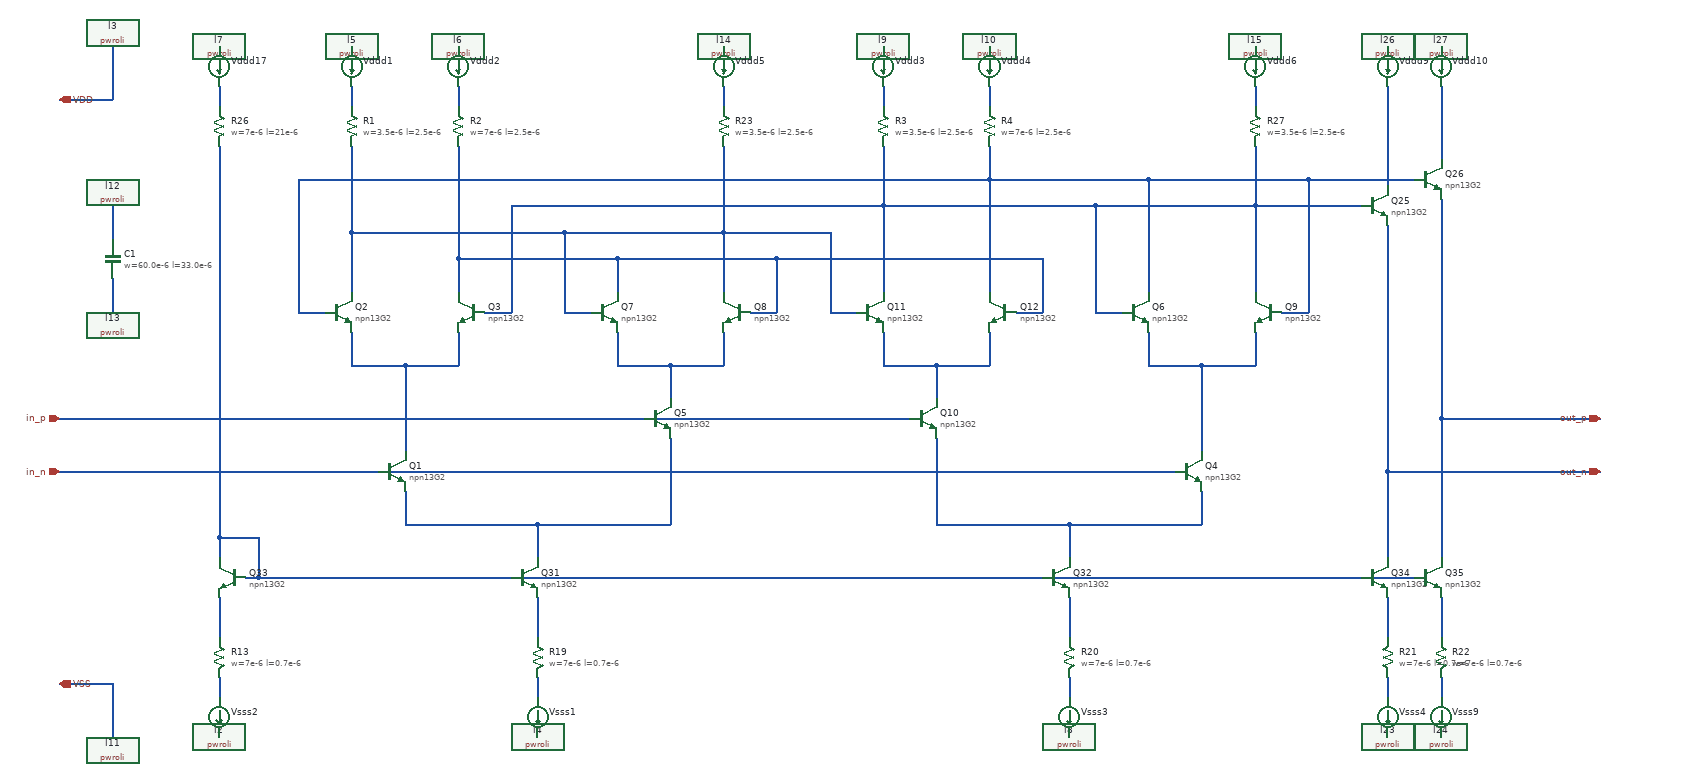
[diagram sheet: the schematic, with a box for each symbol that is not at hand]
v {xschem version=3.4.7RC file_version=1.2
*
* This file is part of XSCHEM,
* a schematic capture and Spice/Vhdl/Verilog netlisting tool for circuit
* simulation.
* Copyright (C) 1998-2023 Stefan Frederik Schippers
*
* This program is free software; you can redistribute it and/or modify
* it under the terms of the GNU General Public License as published by
* the Free Software Foundation; either version 2 of the License, or
* (at your option) any later version.
*
* This program is distributed in the hope that it will be useful,
* but WITHOUT ANY WARRANTY; without even the implied warranty of
* MERCHANTABILITY or FITNESS FOR A PARTICULAR PURPOSE.  See the
* GNU General Public License for more details.
*
* You should have received a copy of the GNU General Public License
* along with this program; if not, write to the Free Software
* Foundation, Inc., 51 Franklin Street, Fifth Floor, Boston, MA 02110-1301 USA
}
G {}
K {}
V {}
S {}
E {}
N 1160 -800 1240 -800 {lab=#net1}
N 1160 -800 1160 -750 {lab=#net1}
N 1080 -800 1160 -800 {lab=#net1}
N 1080 -850 1080 -800 {lab=#net1}
N 1240 -850 1240 -800 {lab=#net1}
N 760 -800 840 -800 {lab=#net2}
N 760 -800 760 -670 {lab=#net2}
N 680 -800 760 -800 {lab=#net2}
N 680 -850 680 -800 {lab=#net2}
N 840 -850 840 -800 {lab=#net2}
N 680 -1000 680 -910 {lab=#net3}
N 840 -960 840 -910 {lab=#net4}
N 680 -1130 680 -1000 {lab=#net3}
N 1240 -1000 1240 -910 {lab=#net3}
N 840 -960 1080 -960 {lab=#net4}
N 840 -1130 840 -960 {lab=#net4}
N 1080 -960 1080 -910 {lab=#net4}
N 1000 -880 1040 -880 {lab=#net3}
N 1000 -1000 1000 -880 {lab=#net3}
N 680 -1000 1000 -1000 {lab=#net3}
N 1080 -960 1320 -960 {lab=#net4}
N 1320 -960 1320 -880 {lab=#net4}
N 1280 -880 1320 -880 {lab=#net4}
N 680 -1220 680 -1190 {lab=VDD}
N 840 -1220 840 -1190 {lab=VDD}
N 1960 -800 2040 -800 {lab=#net5}
N 1960 -800 1960 -670 {lab=#net5}
N 1880 -800 1960 -800 {lab=#net5}
N 1880 -850 1880 -800 {lab=#net5}
N 2040 -850 2040 -800 {lab=#net5}
N 1560 -800 1640 -800 {lab=#net6}
N 1560 -800 1560 -750 {lab=#net6}
N 1480 -800 1560 -800 {lab=#net6}
N 1480 -850 1480 -800 {lab=#net6}
N 1640 -850 1640 -800 {lab=#net6}
N 1480 -1040 1480 -910 {lab=#net7}
N 1640 -1080 1640 -910 {lab=#net8}
N 1800 -1040 2040 -1040 {lab=#net7}
N 1480 -1130 1480 -1040 {lab=#net7}
N 1640 -1130 1640 -1080 {lab=#net8}
N 1880 -1080 1880 -910 {lab=#net8}
N 1800 -880 1840 -880 {lab=#net7}
N 1800 -1040 1800 -880 {lab=#net7}
N 1880 -1080 2120 -1080 {lab=#net8}
N 2120 -1080 2120 -880 {lab=#net8}
N 2080 -880 2120 -880 {lab=#net8}
N 1480 -1220 1480 -1190 {lab=VDD}
N 1640 -1220 1640 -1190 {lab=VDD}
N 1680 -880 1720 -880 {lab=#net4}
N 1000 -1000 1240 -1000 {lab=#net3}
N 600 -880 640 -880 {lab=#net8}
N 880 -880 920 -880 {lab=#net7}
N 1640 -1080 1880 -1080 {lab=#net8}
N 1320 -960 1720 -960 {lab=#net4}
N 1720 -960 1720 -880 {lab=#net4}
N 1240 -1000 1400 -1000 {lab=#net3}
N 1400 -1000 1400 -880 {lab=#net3}
N 1400 -880 1440 -880 {lab=#net3}
N 600 -1080 1640 -1080 {lab=#net8}
N 600 -1080 600 -880 {lab=#net8}
N 920 -1040 920 -880 {lab=#net7}
N 1480 -1040 1800 -1040 {lab=#net7}
N 920 -1040 1480 -1040 {lab=#net7}
N 2240 -640 2240 -510 {lab=out_n}
N 2320 -720 2320 -510 {lab=out_p}
N 2240 -1220 2240 -1070 {lab=VDD}
N 2320 -1220 2320 -1110 {lab=VDD}
N 240 -720 1520 -720 {lab=in_p}
N 960 -560 1160 -560 {lab=#net9}
N 960 -560 960 -510 {lab=#net9}
N 760 -560 960 -560 {lab=#net9}
N 1760 -560 1960 -560 {lab=#net10}
N 1760 -560 1760 -510 {lab=#net10}
N 1560 -560 1760 -560 {lab=#net10}
N 480 -540 480 -510 {lab=#net11}
N 540 -540 540 -480 {lab=#net11}
N 520 -480 540 -480 {lab=#net11}
N 480 -540 540 -540 {lab=#net11}
N 480 -1220 480 -1190 {lab=VDD}
N 480 -1130 480 -540 {lab=#net11}
N 760 -610 760 -560 {lab=#net9}
N 1160 -690 1160 -560 {lab=#net9}
N 1560 -690 1560 -560 {lab=#net10}
N 1960 -610 1960 -560 {lab=#net10}
N 480 -330 480 -300 {lab=VSS}
N 480 -450 480 -390 {lab=#net12}
N 960 -330 960 -300 {lab=VSS}
N 960 -450 960 -390 {lab=#net13}
N 2320 -330 2320 -300 {lab=VSS}
N 2320 -450 2320 -390 {lab=#net14}
N 2240 -330 2240 -300 {lab=VSS}
N 2240 -450 2240 -390 {lab=#net15}
N 1760 -330 1760 -300 {lab=VSS}
N 1760 -450 1760 -390 {lab=#net16}
N 2320 -720 2560 -720 {lab=out_p}
N 2240 -640 2560 -640 {lab=out_n}
N 540 -480 2280 -480 {lab=#net11}
N 240 -640 1920 -640 {lab=in_n}
N 240 -1200 320 -1200 {
lab=VDD}
N 320 -1280 320 -1200 {
lab=VDD}
N 240 -320 320 -320 {
lab=VSS}
N 320 -320 320 -240 {
lab=VSS}
N 2120 -1080 2280 -1080 {lab=#net8}
N 2040 -1040 2200 -1040 {lab=#net7}
N 320 -1040 320 -990 {lab=VDD}
N 320 -930 320 -880 {lab=VSS}
N 1240 -1220 1240 -1190 {lab=VDD}
N 1240 -1130 1240 -1000 {lab=#net3}
N 2040 -1220 2040 -1190 {lab=VDD}
N 2040 -1040 2040 -910 {lab=#net7}
N 2040 -1130 2040 -1040 {lab=#net7}
N 2320 -1050 2320 -720 {lab=out_p}
N 2240 -1010 2240 -640 {lab=out_n}
C {title.sym} 160 -30 0 0 {name=l1 author="om"  net_name=true}
C {npn13G2oli.sym} 1140 -720 0 0 {name=Q5
model=npn13G2
spiceprefix=X
Nx=1
le=900e-9
Sub=VSS}
C {npn13G2oli.sym} 1060 -880 0 0 {name=Q7
model=npn13G2
spiceprefix=X
Nx=1
le=900e-9
Sub=VSS}
C {npn13G2oli.sym} 1260 -880 0 1 {name=Q8
model=npn13G2
spiceprefix=X
Nx=1
le=900e-9
Sub=VSS}
C {pwroli.sym} 960 -240 0 0 {name=l4 lab=VSS}
C {ammeter.sym} 960 -270 0 0 {name=Vsss1 
savecurrent=true
lvs_ignore=short}
C {npn13G2oli.sym} 740 -640 0 0 {name=Q1
model=npn13G2
spiceprefix=X
Nx=1
le=900e-9
Sub=VSS}
C {npn13G2oli.sym} 660 -880 0 0 {name=Q2
model=npn13G2
spiceprefix=X
Nx=1
le=900e-9
Sub=VSS}
C {npn13G2oli.sym} 860 -880 0 1 {name=Q3
model=npn13G2
spiceprefix=X
Nx=1
le=900e-9
Sub=VSS}
C {pwroli.sym} 680 -1280 2 0 {name=l5 lab=VDD
}
C {pwroli.sym} 840 -1280 2 0 {name=l6 lab=VDD
}
C {ammeter.sym} 680 -1250 0 0 {name=Vddd1
savecurrent=true
lvs_ignore=short}
C {ammeter.sym} 840 -1250 0 0 {name=Vddd2
savecurrent=true
lvs_ignore=short}
C {npn13G2oli.sym} 1940 -640 0 0 {name=Q4
model=npn13G2
spiceprefix=X
Nx=1
le=900e-9
Sub=VSS}
C {npn13G2oli.sym} 1860 -880 0 0 {name=Q6
model=npn13G2
spiceprefix=X
Nx=1
le=900e-9
Sub=VSS}
C {npn13G2oli.sym} 2060 -880 0 1 {name=Q9
model=npn13G2
spiceprefix=X
Nx=1
le=900e-9
Sub=VSS}
C {pwroli.sym} 1760 -240 0 0 {name=l8 lab=VSS}
C {ammeter.sym} 1760 -270 0 0 {name=Vsss3 
savecurrent=true
lvs_ignore=short}
C {npn13G2oli.sym} 1540 -720 0 0 {name=Q10
model=npn13G2
spiceprefix=X
Nx=1
le=900e-9
Sub=VSS}
C {npn13G2oli.sym} 1460 -880 0 0 {name=Q11
model=npn13G2
spiceprefix=X
Nx=1
le=900e-9
Sub=VSS}
C {npn13G2oli.sym} 1660 -880 0 1 {name=Q12
model=npn13G2
spiceprefix=X
Nx=1
le=900e-9
Sub=VSS}
C {pwroli.sym} 1480 -1280 2 0 {name=l9 lab=VDD
}
C {pwroli.sym} 1640 -1280 2 0 {name=l10 lab=VDD
}
C {ammeter.sym} 1480 -1250 0 0 {name=Vddd3
savecurrent=true
lvs_ignore=short}
C {ammeter.sym} 1640 -1250 0 0 {name=Vddd4
savecurrent=true
lvs_ignore=short}
C {npn13G2oli.sym} 2220 -1040 0 0 {name=Q25
model=npn13G2
spiceprefix=X
Nx=1
le=900e-9
Sub=VSS}
C {npn13G2oli.sym} 2300 -1080 0 0 {name=Q26
model=npn13G2
spiceprefix=X
Nx=1
le=900e-9
Sub=VSS}
C {pwroli.sym} 2240 -1280 2 0 {name=l26 lab=VDD
}
C {ammeter.sym} 2240 -1250 0 0 {name=Vddd9
savecurrent=true
lvs_ignore=short}
C {pwroli.sym} 2320 -1280 2 0 {name=l27 lab=VDD
}
C {ammeter.sym} 2320 -1250 0 0 {name=Vddd10
savecurrent=true
lvs_ignore=short}
C {npn13G2oli.sym} 940 -480 0 0 {name=Q31
model=npn13G2
spiceprefix=X
Nx=1
le=900e-9
Sub=VSS}
C {npn13G2oli.sym} 1740 -480 0 0 {name=Q32
model=npn13G2
spiceprefix=X
Nx=1
le=900e-9
Sub=VSS}
C {pwroli.sym} 480 -240 0 1 {name=l2 lab=VSS}
C {ammeter.sym} 480 -270 0 1 {name=Vsss2 
savecurrent=true
lvs_ignore=short}
C {npn13G2oli.sym} 500 -480 0 1 {name=Q33
model=npn13G2
spiceprefix=X
Nx=1
le=900e-9
Sub=VSS}
C {pwroli.sym} 480 -1280 2 0 {name=l7 lab=VDD
}
C {ammeter.sym} 480 -1250 0 0 {name=Vddd17
savecurrent=true
lvs_ignore=short}
C {pwroli.sym} 2240 -240 0 0 {name=l23 lab=VSS}
C {ammeter.sym} 2240 -270 0 0 {name=Vsss4 
savecurrent=true
lvs_ignore=short}
C {npn13G2oli.sym} 2220 -480 0 0 {name=Q34
model=npn13G2
spiceprefix=X
Nx=1
le=900e-9
Sub=VSS}
C {pwroli.sym} 2320 -240 0 0 {name=l24 lab=VSS}
C {ammeter.sym} 2320 -270 0 0 {name=Vsss9 
savecurrent=true
lvs_ignore=short}
C {npn13G2oli.sym} 2300 -480 0 0 {name=Q35
model=npn13G2
spiceprefix=X
Nx=1
le=900e-9
Sub=VSS}
C {ngspice_probe.sym} 2320 -520 0 0 {name=r5}
C {ngspice_probe.sym} 2240 -520 0 0 {name=r6}
C {ngspice_probe.sym} 1960 -560 0 0 {name=r7}
C {ngspice_probe.sym} 1960 -480 0 0 {name=r8}
C {ngspice_probe.sym} 1160 -560 0 0 {name=r9}
C {ngspice_probe.sym} 1340 -720 0 0 {name=r10}
C {ngspice_probe.sym} 800 -800 0 0 {name=r11}
C {ngspice_probe.sym} 1180 -800 0 0 {name=r12}
C {ngspice_probe.sym} 1590 -800 0 0 {name=r14}
C {ngspice_probe.sym} 1990 -800 0 0 {name=r15}
C {ngspice_probe.sym} 1120 -1080 0 0 {name=r16}
C {ngspice_probe.sym} 1120 -1040 0 0 {name=r17}
C {ngspice_probe.sym} 480 -600 0 0 {name=r18}
C {ngspice_probe.sym} 960 -390 0 0 {name=r44}
C {ngspice_probe.sym} 480 -390 0 0 {name=r45}
C {ipin.sym} 240 -720 0 0 {name=p3 lab=in_p
}
C {ipin.sym} 240 -640 0 0 {name=p1 lab=in_n
}
C {iopin.sym} 240 -1200 0 1 {name=p9 lab=VDD}
C {pwroli.sym} 320 -1280 2 0 {name=l3 lab=VDD
}
C {iopin.sym} 240 -320 0 1 {name=p8 lab=VSS

}
C {pwroli.sym} 320 -240 0 0 {name=l11 lab=VSS}
C {opin.sym} 2560 -720 2 1 {name=p5 lab=out_p

}
C {opin.sym} 2560 -640 2 1 {name=p2 lab=out_n

}
C {ngspice_probe.sym} 1120 -1000 0 0 {name=r24}
C {ngspice_probe.sym} 1120 -960 0 0 {name=r25}
C {rppd.sym} 480 -1160 0 0 {name=R26
w=7e-6
l=21e-6
model=rppd
spiceprefix=X
b=0
m=1
}
C {rppd.sym} 680 -1160 0 0 {name=R1
w=3.5e-6
l=2.5e-6
model=rppd
spiceprefix=X
b=0
m=1
}
C {rppd.sym} 840 -1160 0 0 {name=R2
w=7e-6
l=2.5e-6
model=rppd
spiceprefix=X
b=0
m=1
}
C {rppd.sym} 1480 -1160 0 0 {name=R3
w=3.5e-6
l=2.5e-6
model=rppd
spiceprefix=X
b=0
m=1
}
C {rppd.sym} 1640 -1160 0 0 {name=R4
w=7e-6
l=2.5e-6
model=rppd
spiceprefix=X
b=0
m=1
}
C {rppd.sym} 480 -360 0 0 {name=R13
w=7e-6
l=0.7e-6
model=rppd
spiceprefix=X
b=0
m=1
}
C {rppd.sym} 960 -360 0 0 {name=R19
w=7e-6
l=0.7e-6
model=rppd
spiceprefix=X
b=0
m=1
}
C {rppd.sym} 1760 -360 0 0 {name=R20
w=7e-6
l=0.7e-6
model=rppd
spiceprefix=X
b=0
m=1
}
C {rppd.sym} 2240 -360 2 0 {name=R21
w=7e-6
l=0.7e-6
model=rppd
spiceprefix=X
b=0
m=1
}
C {rppd.sym} 2320 -360 0 0 {name=R22
w=7e-6
l=0.7e-6
model=rppd
spiceprefix=X
b=0
m=1
}
C {launcher.sym} 220 -160 0 0 {name=h1
descr="write LVS netlist"
tclcommand="
	xschem set netlist_type spice
	set lvs_ignore 1
	set lvs_netlist 1
	set spiceprefix 0
	set last_local_netlist_dir $local_netlist_dir
	set local_netlist_dir 0
	xschem netlist [xschem get current_name].cdl
	set local_netlist_dir $last_local_netlist_dir

"
}
C {cap_cmim.sym} 320 -960 0 0 {name=C1
model=cap_cmim
w=60.0e-6
l=33.0e-6
m=1
spiceprefix=X}
C {pwroli.sym} 320 -1040 2 0 {name=l12 lab=VDD
}
C {pwroli.sym} 320 -880 0 1 {name=l13 lab=VSS}
C {pwroli.sym} 1240 -1280 2 0 {name=l14 lab=VDD
}
C {ammeter.sym} 1240 -1250 0 0 {name=Vddd5
savecurrent=true
lvs_ignore=short}
C {rppd.sym} 1240 -1160 0 0 {name=R23
w=3.5e-6
l=2.5e-6
model=rppd
spiceprefix=X
b=0
m=1
}
C {pwroli.sym} 2040 -1280 2 0 {name=l15 lab=VDD
}
C {ammeter.sym} 2040 -1250 0 0 {name=Vddd6
savecurrent=true
lvs_ignore=short}
C {rppd.sym} 2040 -1160 0 0 {name=R27
w=3.5e-6
l=2.5e-6
model=rppd
spiceprefix=X
b=0
m=1
}
